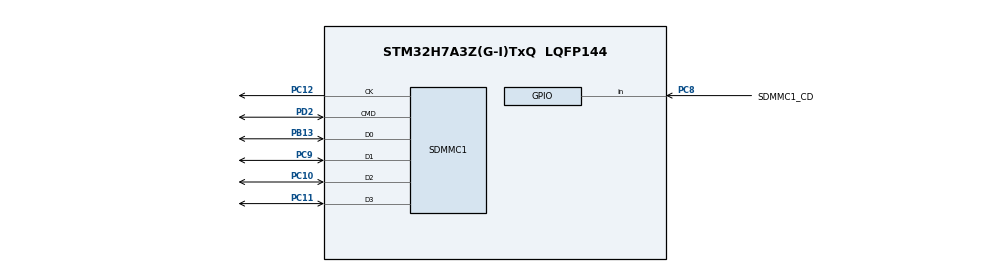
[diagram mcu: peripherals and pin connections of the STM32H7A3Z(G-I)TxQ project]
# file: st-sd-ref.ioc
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CORTEX_M7.default_mode_Activation=1
FATFS.BSP.number=1
FATFS.USE_DMA_CODE_SD=0
FATFS._USE_LFN=3
FATFS0.BSP.STBoard=false
FATFS0.BSP.api=Unknown
FATFS0.BSP.instance=PC8
FATFS0.BSP.ip=GPIO
FATFS0.BSP.mode=Input
FATFS0.BSP.name=Detect_SDIO
FATFS0.BSP.solution=PC8
Mcu.Family=STM32H7
Mcu.Name=STM32H7A3Z(G-I)TxQ
Mcu.Package=LQFP144
NUCLEO-H7A3ZI-Q.BUTTON=1
NUCLEO-H7A3ZI-Q.LD1=true
NUCLEO-H7A3ZI-Q.LD2=true
NUCLEO-H7A3ZI-Q.LD3=true
NUCLEO-H7A3ZI-Q.VCP=true
NVIC.EXTI15_10_IRQn=true\:0\:0\:false\:false\:true\:false\:true\:true
NVIC.PriorityGroup=NVIC_PRIORITYGROUP_4
NVIC.SDMMC1_IRQn=true\:0\:0\:false\:false\:true\:true\:true\:true
PB13.Mode=SD_4_bits_Wide_bus
PB13.Signal=SDMMC1_D0
PC10.Mode=SD_4_bits_Wide_bus
PC10.Signal=SDMMC1_D2
PC11.Mode=SD_4_bits_Wide_bus
PC11.Signal=SDMMC1_D3
PC12.Mode=SD_4_bits_Wide_bus
PC12.Signal=SDMMC1_CK
PC14-OSC32_IN.GPIO_Label=OSC32_IN
PC14-OSC32_IN.Signal=RCC_OSC32_IN
PC15-OSC32_OUT.GPIO_Label=OSC32_OUT
PC15-OSC32_OUT.Signal=RCC_OSC32_OUT
PC8.GPIO_Label=SDMMC1_CD
PC8.Signal=GPIO_Input
PC9.Mode=SD_4_bits_Wide_bus
PC9.Signal=SDMMC1_D1
PD2.Mode=SD_4_bits_Wide_bus
PD2.Signal=SDMMC1_CMD
PD8.Signal=USART3_TX
PD9.Signal=USART3_RX
PH0-OSC_IN.GPIO_Label=PH0-MCU
PH0-OSC_IN.Signal=RCC_OSC_IN
PH1-OSC_OUT.GPIO_Label=PH1-MCU
PH1-OSC_OUT.Signal=RCC_OSC_OUT
ProjectManager.HeapSize=0x200
ProjectManager.StackSize=0x400
ProjectManager.TargetToolchain=CMake
RCC.ADCFreq_Value=72000000
RCC.APB1Freq_Value=90000000
RCC.APB2Freq_Value=90000000
RCC.APB3Freq_Value=90000000
RCC.APB4Freq_Value=90000000
RCC.CDPPRE=RCC_APB3_DIV2
RCC.CDPPRE1=RCC_APB1_DIV2
RCC.CDPPRE2=RCC_APB2_DIV2
RCC.CortexFreq_Value=180000000
RCC.DIVM1=4
RCC.DIVM2=8
RCC.DIVM3=1
RCC.DIVN1=180
RCC.DIVN2=144
RCC.DIVN3=24
RCC.DIVQ1=4
RCC.DIVR2=4
RCC.HCLKFreq_Value=180000000
RCC.HSE_VALUE=8000000
RCC.HSIDiv=RCC_PLLSAIDIVR_8
RCC.PLLFRACN=0
RCC.PWR_Regulator_Voltage_Scale=PWR_REGULATOR_VOLTAGE_SCALE0
RCC.SDMMC1CLockSelection=RCC_SDMMCCLKSOURCE_PLL2
RCC.SRDPPRE=RCC_APB4_DIV2
RCC.SYSCLKFreq_VALUE=180000000
RCC.SYSCLKSource=RCC_SYSCLKSOURCE_PLLCLK
RCC.SupplySource=PWR_DIRECT_SMPS_SUPPLY
RCC.USBCLockSelection=RCC_USBCLKSOURCE_HSI48
RCC.USBFreq_Value=48000000
SDMMC1.HardwareFlowControl=SDMMC_HARDWARE_FLOW_CONTROL_ENABLE
VP_FATFS_VS_SDIO.Mode=SDIO
VP_MEMORYMAP_VS_MEMORYMAP.Mode=CurAppReg
VP_NUCLEO-H7A3ZI-Q_VS_BSP_COMMON.Mode=COMMON
board=NUCLEO-H7A3ZI-Q

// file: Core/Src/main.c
/* USER CODE BEGIN Header */
/**
  ******************************************************************************
  * @file           : main.c
  * @brief          : Main program body
  ******************************************************************************
  * @attention
  *
  * Copyright (c) 2026 STMicroelectronics.
  * All rights reserved.
  *
  * This software is licensed under terms that can be found in the LICENSE file
  * in the root directory of this software component.
  * If no LICENSE file comes with this software, it is provided AS-IS.
  *
  ******************************************************************************
  */
/* USER CODE END Header */
#include "main.h"
#include "fatfs.h"

/* USER CODE BEGIN Includes */
#include "sd_diag.h" /* repro + diagnostics - see sd_diag.c/README.md */
/* USER CODE END Includes */

COM_InitTypeDef BspCOMInit;

SD_HandleTypeDef hsd1;

void SystemClock_Config(void);
static void MPU_Config(void);
static void MX_GPIO_Init(void);
static void MX_SDMMC1_SD_Init(void);

int main(void)
{

  /* MPU Configuration--------------------------------------------------------*/
  MPU_Config();

  /* MCU Configuration--------------------------------------------------------*/

  /* Reset of all peripherals, Initializes the Flash interface and the Systick. */
  HAL_Init();

  /* Configure the system clock */
  SystemClock_Config();

  /* Initialize all configured peripherals */
  MX_GPIO_Init();
  MX_SDMMC1_SD_Init();
  MX_FATFS_Init();

  /* Initialize leds */
  BSP_LED_Init(LED_GREEN);
  BSP_LED_Init(LED_YELLOW);
  BSP_LED_Init(LED_RED);

  /* Initialize USER push-button, will be used to trigger an interrupt each time it's pressed.*/
  BSP_PB_Init(BUTTON_USER, BUTTON_MODE_EXTI);

  /* Initialize COM1 port (115200, 8 bits (7-bit data + 1 stop bit), no parity */
  BspCOMInit.BaudRate   = 115200;
  BspCOMInit.WordLength = COM_WORDLENGTH_8B;
  BspCOMInit.StopBits   = COM_STOPBITS_1;
  BspCOMInit.Parity     = COM_PARITY_NONE;
  BspCOMInit.HwFlowCtl  = COM_HWCONTROL_NONE;
  if (BSP_COM_Init(COM1, &BspCOMInit) != BSP_ERROR_NONE)
  {
    Error_Handler();
  }

  /* Infinite loop */
  /* USER CODE BEGIN WHILE */
  SD_Repro_MountAndListRoot(); // minimal repro - see README.md

  // Diagnostic helpers used while investigating the failure above -
  // uncomment individually as needed. See FINDINGS.md for what each one
  // showed.
  // SD_Diag_DumpCardInfo();       // print CID/CSD and card info
  // SD_Diag_RawBlockRead(8192);   // register-level diag read (STA/DCOUNT) of one block
  // SD_Diag_DmaReadTest(8192);    // IDMA-mode read of one block
  // SD_Diag_DlybSweep();          // sweep the SDMMC1 RX delay-block's sampling phase (~10s)

  while (1)
  {

    /* USER CODE END WHILE */

  }
}

void SystemClock_Config(void)
{
  RCC_OscInitTypeDef RCC_OscInitStruct = {0};
  RCC_ClkInitTypeDef RCC_ClkInitStruct = {0};

  /*AXI clock gating */
  RCC->CKGAENR = 0xE003FFFF;

  /** Supply configuration update enable
  */
  HAL_PWREx_ConfigSupply(PWR_DIRECT_SMPS_SUPPLY);

  /** Configure the main internal regulator output voltage
  */
  __HAL_PWR_VOLTAGESCALING_CONFIG(PWR_REGULATOR_VOLTAGE_SCALE0);

  while(!__HAL_PWR_GET_FLAG(PWR_FLAG_VOSRDY)) {}

  /** Initializes the RCC Oscillators according to the specified parameters
  * in the RCC_OscInitTypeDef structure.
  */
  RCC_OscInitStruct.OscillatorType = RCC_OSCILLATORTYPE_HSI;
  RCC_OscInitStruct.HSIState = RCC_HSI_DIV8;
  RCC_OscInitStruct.HSICalibrationValue = 64;
  RCC_OscInitStruct.PLL.PLLState = RCC_PLL_ON;
  RCC_OscInitStruct.PLL.PLLSource = RCC_PLLSOURCE_HSI;
  RCC_OscInitStruct.PLL.PLLM = 4;
  RCC_OscInitStruct.PLL.PLLN = 180;
  RCC_OscInitStruct.PLL.PLLP = 2;
  RCC_OscInitStruct.PLL.PLLQ = 4;
  RCC_OscInitStruct.PLL.PLLR = 2;
  RCC_OscInitStruct.PLL.PLLRGE = RCC_PLL1VCIRANGE_1;
  RCC_OscInitStruct.PLL.PLLVCOSEL = RCC_PLL1VCOWIDE;
  RCC_OscInitStruct.PLL.PLLFRACN = 0;
  if (HAL_RCC_OscConfig(&RCC_OscInitStruct) != HAL_OK)
  {
    Error_Handler();
  }

  /** Initializes the CPU, AHB and APB buses clocks
  */
  RCC_ClkInitStruct.ClockType = RCC_CLOCKTYPE_HCLK|RCC_CLOCKTYPE_SYSCLK
                              |RCC_CLOCKTYPE_PCLK1|RCC_CLOCKTYPE_PCLK2
                              |RCC_CLOCKTYPE_D3PCLK1|RCC_CLOCKTYPE_D1PCLK1;
  RCC_ClkInitStruct.SYSCLKSource = RCC_SYSCLKSOURCE_PLLCLK;
  RCC_ClkInitStruct.SYSCLKDivider = RCC_SYSCLK_DIV1;
  RCC_ClkInitStruct.AHBCLKDivider = RCC_HCLK_DIV1;
  RCC_ClkInitStruct.APB3CLKDivider = RCC_APB3_DIV2;
  RCC_ClkInitStruct.APB1CLKDivider = RCC_APB1_DIV2;
  RCC_ClkInitStruct.APB2CLKDivider = RCC_APB2_DIV2;
  RCC_ClkInitStruct.APB4CLKDivider = RCC_APB4_DIV2;

  if (HAL_RCC_ClockConfig(&RCC_ClkInitStruct, FLASH_LATENCY_4) != HAL_OK)
  {
    Error_Handler();
  }
}

static void MX_SDMMC1_SD_Init(void)
{

  hsd1.Instance = SDMMC1;
  hsd1.Init.ClockEdge = SDMMC_CLOCK_EDGE_RISING;
  hsd1.Init.ClockPowerSave = SDMMC_CLOCK_POWER_SAVE_DISABLE;
  hsd1.Init.HardwareFlowControl = SDMMC_HARDWARE_FLOW_CONTROL_ENABLE;
  // ST support ticket 00268848 suggested a known CubeMX+FatFs issue where a
  // project initialized directly in 4-bit mode fails, but works if
  // HAL_SD_Init() is called with 1-bit first and then switched to 4-bit via
  // a separate HAL_SD_ConfigWideBusOperation() call (BSP_SD_Init() in
  // FATFS/Target/bsp_driver_sd.c, unmodified CubeMX output, already does
  // exactly that second step - it just was never actually exercised as
  // "1-bit then switch" because this handle was pre-set to 4-bit before
  // ever calling HAL_SD_Init() the first time). Tested: no effect, byte-
  // for-byte identical DCRCFAIL signature. Left set to 1B anyway since it's
  // the more defensive init order regardless - see FINDINGS.md.
  hsd1.Init.BusWide = SDMMC_BUS_WIDE_1B;
  hsd1.Init.ClockDiv = 0;
  if (HAL_SD_Init(&hsd1) != HAL_OK)
  {
    Error_Handler();
  }

}

static void MX_GPIO_Init(void)
{
  GPIO_InitTypeDef GPIO_InitStruct = {0};

  /* GPIO Ports Clock Enable */
  __HAL_RCC_GPIOC_CLK_ENABLE();
  __HAL_RCC_GPIOH_CLK_ENABLE();
  __HAL_RCC_GPIOB_CLK_ENABLE();
  __HAL_RCC_GPIOD_CLK_ENABLE();

  /*Configure GPIO pin : SDMMC1_CD_Pin */
  GPIO_InitStruct.Pin = SDMMC1_CD_Pin;
  GPIO_InitStruct.Mode = GPIO_MODE_INPUT;
  GPIO_InitStruct.Pull = GPIO_NOPULL;
  HAL_GPIO_Init(SDMMC1_CD_GPIO_Port, &GPIO_InitStruct);

}

 /* MPU Configuration */

void MPU_Config(void)
{
  MPU_Region_InitTypeDef MPU_InitStruct = {0};

  /* Disables the MPU */
  HAL_MPU_Disable();

  /** Initializes and configures the Region and the memory to be protected
  */
  MPU_InitStruct.Enable = MPU_REGION_ENABLE;
  MPU_InitStruct.Number = MPU_REGION_NUMBER0;
  MPU_InitStruct.BaseAddress = 0x0;
  MPU_InitStruct.Size = MPU_REGION_SIZE_4GB;
  MPU_InitStruct.SubRegionDisable = 0x87;
  MPU_InitStruct.TypeExtField = MPU_TEX_LEVEL0;
  MPU_InitStruct.AccessPermission = MPU_REGION_NO_ACCESS;
  MPU_InitStruct.DisableExec = MPU_INSTRUCTION_ACCESS_DISABLE;
  MPU_InitStruct.IsShareable = MPU_ACCESS_SHAREABLE;
  MPU_InitStruct.IsCacheable = MPU_ACCESS_NOT_CACHEABLE;
  MPU_InitStruct.IsBufferable = MPU_ACCESS_NOT_BUFFERABLE;

  HAL_MPU_ConfigRegion(&MPU_InitStruct);
  /* Enables the MPU */
  HAL_MPU_Enable(MPU_PRIVILEGED_DEFAULT);

}

void Error_Handler(void)
{
  __disable_irq();
  while (1)
  {
  }
}
